VERSION 5.7 ;
  NOWIREEXTENSIONATPIN ON ;
  DIVIDERCHAR "/" ;
  BUSBITCHARS "[]" ;
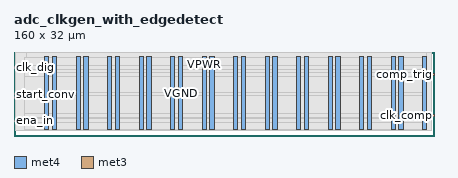
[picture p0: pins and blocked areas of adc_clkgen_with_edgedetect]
MACRO adc_clkgen_with_edgedetect
  CLASS BLOCK ;
  FOREIGN adc_clkgen_with_edgedetect ;
  ORIGIN 0.000 0.000 ;
  SIZE 160.000 BY 32.000 ;
  PIN VGND
    DIRECTION INOUT ;
    USE GROUND ;
    PORT
      LAYER met4 ;
        RECT 14.660 2.480 16.260 30.160 ;
    END
    PORT
      LAYER met4 ;
        RECT 26.660 2.480 28.260 30.160 ;
    END
    PORT
      LAYER met4 ;
        RECT 38.660 2.480 40.260 30.160 ;
    END
    PORT
      LAYER met4 ;
        RECT 50.660 2.480 52.260 30.160 ;
    END
    PORT
      LAYER met4 ;
        RECT 62.660 2.480 64.260 30.160 ;
    END
    PORT
      LAYER met4 ;
        RECT 74.660 2.480 76.260 30.160 ;
    END
    PORT
      LAYER met4 ;
        RECT 86.660 2.480 88.260 30.160 ;
    END
    PORT
      LAYER met4 ;
        RECT 98.660 2.480 100.260 30.160 ;
    END
    PORT
      LAYER met4 ;
        RECT 110.660 2.480 112.260 30.160 ;
    END
    PORT
      LAYER met4 ;
        RECT 122.660 2.480 124.260 30.160 ;
    END
    PORT
      LAYER met4 ;
        RECT 134.660 2.480 136.260 30.160 ;
    END
    PORT
      LAYER met4 ;
        RECT 146.660 2.480 148.260 30.160 ;
    END
  END VGND
  PIN VPWR
    DIRECTION INOUT ;
    USE POWER ;
    PORT
      LAYER met4 ;
        RECT 11.660 2.480 13.260 30.160 ;
    END
    PORT
      LAYER met4 ;
        RECT 23.660 2.480 25.260 30.160 ;
    END
    PORT
      LAYER met4 ;
        RECT 35.660 2.480 37.260 30.160 ;
    END
    PORT
      LAYER met4 ;
        RECT 47.660 2.480 49.260 30.160 ;
    END
    PORT
      LAYER met4 ;
        RECT 59.660 2.480 61.260 30.160 ;
    END
    PORT
      LAYER met4 ;
        RECT 71.660 2.480 73.260 30.160 ;
    END
    PORT
      LAYER met4 ;
        RECT 83.660 2.480 85.260 30.160 ;
    END
    PORT
      LAYER met4 ;
        RECT 95.660 2.480 97.260 30.160 ;
    END
    PORT
      LAYER met4 ;
        RECT 107.660 2.480 109.260 30.160 ;
    END
    PORT
      LAYER met4 ;
        RECT 119.660 2.480 121.260 30.160 ;
    END
    PORT
      LAYER met4 ;
        RECT 131.660 2.480 133.260 30.160 ;
    END
    PORT
      LAYER met4 ;
        RECT 143.660 2.480 145.260 30.160 ;
    END
    PORT
      LAYER met4 ;
        RECT 155.660 2.480 157.260 30.160 ;
    END
  END VPWR
  PIN clk_comp
    DIRECTION OUTPUT TRISTATE ;
    USE SIGNAL ;
    PORT
      LAYER met3 ;
        RECT 156.000 7.520 160.000 8.120 ;
    END
  END clk_comp
  PIN clk_dig
    DIRECTION OUTPUT TRISTATE ;
    USE SIGNAL ;
    PORT
      LAYER met3 ;
        RECT 0.000 25.880 4.000 26.480 ;
    END
  END clk_dig
  PIN comp_trig
    DIRECTION INPUT ;
    USE SIGNAL ;
    PORT
      LAYER met3 ;
        RECT 156.000 23.160 160.000 23.760 ;
    END
  END comp_trig
  PIN ena_in
    DIRECTION INPUT ;
    USE SIGNAL ;
    PORT
      LAYER met3 ;
        RECT 0.000 5.480 4.000 6.080 ;
    END
  END ena_in
  PIN start_conv
    DIRECTION INPUT ;
    USE SIGNAL ;
    PORT
      LAYER met3 ;
        RECT 0.000 15.680 4.000 16.280 ;
    END
  END start_conv
  OBS
      LAYER li1 ;
        RECT 0.460 2.635 159.160 30.005 ;
      LAYER met1 ;
        RECT 0.460 2.080 159.160 31.920 ;
      LAYER met2 ;
        RECT 4.690 2.050 157.230 31.950 ;
      LAYER met3 ;
        RECT 4.000 26.880 157.250 30.085 ;
        RECT 4.400 25.480 157.250 26.880 ;
        RECT 4.000 24.160 157.250 25.480 ;
        RECT 4.000 22.760 155.600 24.160 ;
        RECT 4.000 16.680 157.250 22.760 ;
        RECT 4.400 15.280 157.250 16.680 ;
        RECT 4.000 8.520 157.250 15.280 ;
        RECT 4.000 7.120 155.600 8.520 ;
        RECT 4.000 6.480 157.250 7.120 ;
        RECT 4.400 5.080 157.250 6.480 ;
        RECT 4.000 2.555 157.250 5.080 ;
  END
END adc_clkgen_with_edgedetect
END LIBRARY

